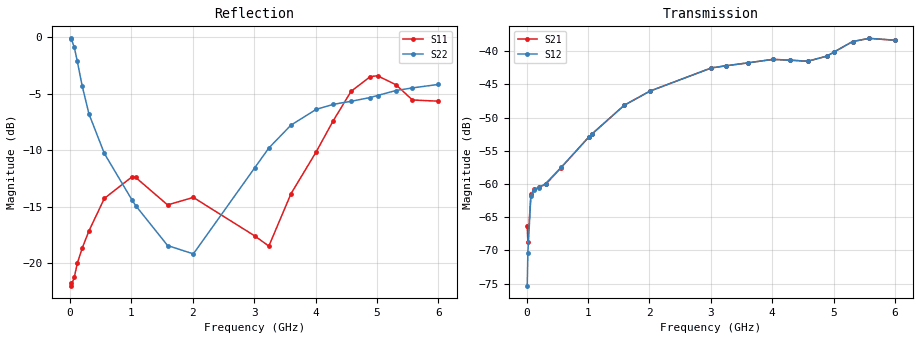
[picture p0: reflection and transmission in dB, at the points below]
!Agilent Technologies,N5230A,MY45001650,A.07.50.48
!Agilent N5230A: A.07.50.48
!Date: Saturday, July 08, 2017 15:50:19
!Correction: S11(Full 2 Port(1,2))
!S21(Full 2 Port(1,2))
!S12(Full 2 Port(1,2))
!S22(Full 2 Port(1,2))
!S2P File: Measurements: S11, S21, S12, S22:
# Hz S  dB  R 50
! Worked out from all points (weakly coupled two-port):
!   600 points, 10 MHz to 6 GHz, reference 50 ohm
!   highest |S21| = -38.07 dB at 5.58 GHz (marker M1); lowest = -68.7 dB at 20 MHz (marker M2)
!   lowest |S11| = -22.0 dB at 20 MHz (marker M3), VSWR 1.17, Z = 58.6 - j1.29 ohm
!   |S11| at or under -10 dB: start of sweep to 4.026 GHz
!   |S22| runs from -19.6 to -0.1 dB; largest |S21 - S12| = 0.00065
!   S11 on the Smith chart (normalised r, x): 10 MHz: 1.18, -0.02; 1.07 GHz: 0.61, -0.01; 4.29 GHz: 0.99, +0.94; 4.89 GHz: 2.78, +2.41; 6 GHz: 2.73, -1.04
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1e7  -21.70 -6.4  -66.37 85.9  -75.32 -102.7  -0.11 -5.5
2e7  -21.97 -7.9  -68.72 64.3  -70.36 131.2  -0.14 -10.5
7e7  -21.22 -25.6  -61.58 15.1  -61.74 15.6  -0.89 -34.7
1.2e8  -19.99 -40.1  -60.83 -18.1  -60.87 -19.2  -2.15 -53.9
2e8  -18.64 -61.7  -60.50 -50.2  -60.54 -49.9  -4.34 -77.2
3.1e8  -17.12 -87.5  -60.07 -78.4  -59.93 -77.6  -6.80 -99.0
5.6e8  -14.26 -126.8  -57.57 -119.3  -57.51 -119.0  -10.28 -129.1
1.01e9  -12.35 -171.2  -52.96 -172.5  -52.96 -172.5  -14.39 -154.8
1.07e9  -12.40 -178.5  -52.44 -178.6  -52.41 -178.8  -14.89 -157.9
1.59e9  -14.83 160.3  -48.14 128.5  -48.15 128.4  -18.42 -171.1
2.01e9  -14.17 157.3  -46.01 88.5  -46.01 88.4  -19.16 -169.6
3.01e9  -17.57 149.9  -42.52 3.6  -42.52 3.5  -11.55 168.4
3.24e9  -18.47 159.8  -42.21 -15.8  -42.21 -15.8  -9.80 161.9
3.6e9  -13.85 141.6  -41.77 -43.7  -41.76 -43.7  -7.78 152.1
4.01e9  -10.15 88.6  -41.23 -76.9  -41.24 -77.0  -6.39 139.8
4.29e9  -7.38 65.2  -41.35 -99.6  -41.36 -99.7  -5.94 130.9
4.58e9  -4.79 43.2  -41.51 -118.7  -41.52 -118.7  -5.67 120.7
4.89e9  -3.50 21.0  -40.75 -137.6  -40.74 -137.5  -5.34 107.3
5.01e9  -3.41 13.7  -40.12 -146.3  -40.11 -146.3  -5.16 102.3
5.31e9  -4.21 -0.8  -38.55 -174.5  -38.55 -174.5  -4.72 88.2
5.58e9  -5.56 -4.7  -38.07 154.0  -38.07 154.0  -4.49 74.7
6e9  -5.66 -15.4  -38.36 116.6  -38.34 116.6  -4.18 52.4
